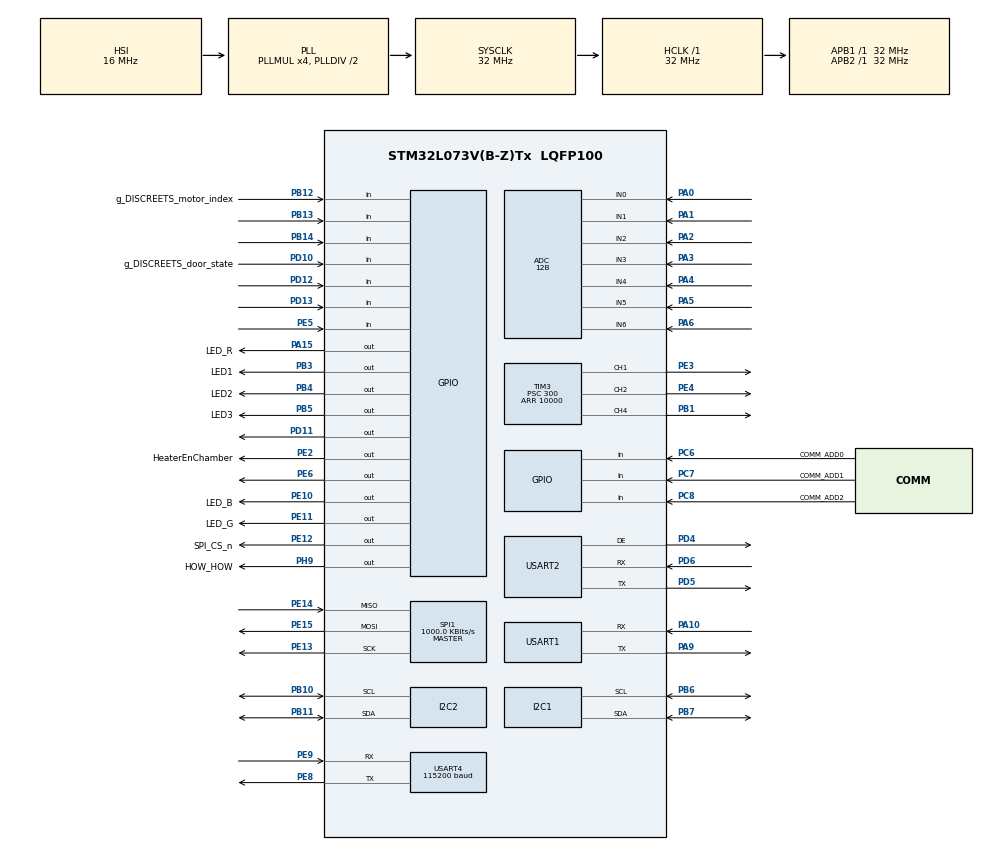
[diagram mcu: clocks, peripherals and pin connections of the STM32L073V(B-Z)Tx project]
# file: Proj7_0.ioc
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ADC.ClockPrescaler=ADC_CLOCK_SYNC_PCLK_DIV2
ADC.ContinuousConvMode=DISABLE
ADC.DMAContinuousRequests=DISABLE
ADC.DataAlign=ADC_DATAALIGN_RIGHT
ADC.DiscontinuousConvMode=DISABLE
ADC.EOCSelection=ADC_EOC_SINGLE_CONV
ADC.EnableAnalogWatchDog=false
ADC.ExternalTrigConv=ADC_SOFTWARE_START
ADC.ExternalTrigConvEdge=ADC_EXTERNALTRIGCONVEDGE_NONE
ADC.LowPowerAutoPowerOff=DISABLE
ADC.LowPowerAutoWait=DISABLE
ADC.LowPowerFrequencyMode=DISABLE
ADC.Overrun=ADC_OVR_DATA_PRESERVED
ADC.OversamplingMode=ENABLE
ADC.Ratio=ADC_OVERSAMPLING_RATIO_16
ADC.Resolution=ADC_RESOLUTION_12B
ADC.RightBitShift=ADC_RIGHTBITSHIFT_4
ADC.SamplingTime=ADC_SAMPLETIME_1CYCLE_5
ADC.ScanConvMode=ADC_SCAN_DIRECTION_FORWARD
Dma.ADC.0.Direction=DMA_PERIPH_TO_MEMORY
Dma.ADC.0.Instance=DMA1_Channel1
Dma.ADC.0.MemDataAlignment=DMA_MDATAALIGN_WORD
Dma.ADC.0.MemInc=DMA_MINC_ENABLE
Dma.ADC.0.Mode=DMA_NORMAL
Dma.ADC.0.PeriphDataAlignment=DMA_PDATAALIGN_HALFWORD
Dma.ADC.0.PeriphInc=DMA_PINC_DISABLE
Dma.ADC.0.Priority=DMA_PRIORITY_HIGH
Dma.Request0=ADC
Dma.Request1=USART1_TX
Dma.Request2=USART2_RX
Dma.Request3=USART2_TX
Dma.USART1_TX.1.Direction=DMA_MEMORY_TO_PERIPH
Dma.USART1_TX.1.Instance=DMA1_Channel2
Dma.USART1_TX.1.MemDataAlignment=DMA_MDATAALIGN_BYTE
Dma.USART1_TX.1.MemInc=DMA_MINC_ENABLE
Dma.USART1_TX.1.Mode=DMA_NORMAL
Dma.USART1_TX.1.PeriphDataAlignment=DMA_PDATAALIGN_BYTE
Dma.USART1_TX.1.PeriphInc=DMA_PINC_DISABLE
Dma.USART1_TX.1.Priority=DMA_PRIORITY_LOW
Dma.USART2_RX.2.Direction=DMA_PERIPH_TO_MEMORY
Dma.USART2_RX.2.Instance=DMA1_Channel5
Dma.USART2_RX.2.MemDataAlignment=DMA_MDATAALIGN_BYTE
Dma.USART2_RX.2.MemInc=DMA_MINC_ENABLE
Dma.USART2_RX.2.Mode=DMA_NORMAL
Dma.USART2_RX.2.PeriphDataAlignment=DMA_PDATAALIGN_BYTE
Dma.USART2_RX.2.PeriphInc=DMA_PINC_DISABLE
Dma.USART2_RX.2.Priority=DMA_PRIORITY_VERY_HIGH
Dma.USART2_TX.3.Direction=DMA_MEMORY_TO_PERIPH
Dma.USART2_TX.3.Instance=DMA1_Channel4
Dma.USART2_TX.3.MemDataAlignment=DMA_MDATAALIGN_BYTE
Dma.USART2_TX.3.MemInc=DMA_MINC_ENABLE
Dma.USART2_TX.3.Mode=DMA_NORMAL
Dma.USART2_TX.3.PeriphDataAlignment=DMA_PDATAALIGN_BYTE
Dma.USART2_TX.3.PeriphInc=DMA_PINC_DISABLE
Dma.USART2_TX.3.Priority=DMA_PRIORITY_LOW
I2C1.Speed=50
I2C1.Timing=0x202029A8
I2C2.Timing=0x00707CBB
Mcu.Family=STM32L0
Mcu.Name=STM32L073V(B-Z)Tx
Mcu.Package=LQFP100
NVIC.DMA1_Channel1_IRQn=true\:0\:0\:false\:false\:true\:false
NVIC.DMA1_Channel2_3_IRQn=true\:0\:0\:false\:false\:true\:false
NVIC.DMA1_Channel4_5_6_7_IRQn=true\:0\:0\:false\:false\:true\:false
NVIC.I2C1_IRQn=true\:0\:0\:false\:false\:true\:true
NVIC.I2C2_IRQn=true\:0\:0\:false\:false\:true\:true
NVIC.USART1_IRQn=true\:0\:0\:false\:false\:true\:true
NVIC.USART2_IRQn=true\:0\:0\:false\:false\:true\:true
NVIC.USART4_5_IRQn=true\:0\:0\:false\:false\:true\:true
PA0.GPIO_Mode=GPIO_MODE_ANALOG
PA0.GPIO_PuPd=GPIO_NOPULL
PA0.Mode=IN0
PA0.Signal=ADC_IN0
PA1.GPIO_Mode=GPIO_MODE_ANALOG
PA1.GPIO_PuPd=GPIO_NOPULL
PA1.Mode=IN1
PA1.Signal=ADC_IN1
PA10.GPIO_ModeDefaultPP=GPIO_MODE_AF_PP
PA10.GPIO_PuPd=GPIO_NOPULL
PA10.GPIO_Speed=GPIO_SPEED_FREQ_VERY_HIGH
PA10.Mode=Asynchronous
PA10.Signal=USART1_RX
PA13.Mode=Serial_Wire
PA13.Signal=SYS_SWDIO
PA14.Mode=Serial_Wire
PA14.Signal=SYS_SWCLK
PA15.GPIO_Label=LED_R
PA15.Signal=GPIO_Output
PA2.GPIO_Mode=GPIO_MODE_ANALOG
PA2.GPIO_PuPd=GPIO_NOPULL
PA2.Mode=IN2
PA2.Signal=ADC_IN2
PA3.GPIO_Mode=GPIO_MODE_ANALOG
PA3.GPIO_PuPd=GPIO_NOPULL
PA3.Mode=IN3
PA3.Signal=ADC_IN3
PA4.GPIO_Mode=GPIO_MODE_ANALOG
PA4.GPIO_PuPd=GPIO_NOPULL
PA4.Mode=IN4
PA4.Signal=ADC_IN4
PA5.GPIO_Mode=GPIO_MODE_ANALOG
PA5.GPIO_PuPd=GPIO_NOPULL
PA5.Mode=IN5
PA5.Signal=ADC_IN5
PA6.GPIO_Mode=GPIO_MODE_ANALOG
PA6.GPIO_PuPd=GPIO_NOPULL
PA6.Mode=IN6
PA6.Signal=ADC_IN6
PA9.Mode=Asynchronous
PA9.Signal=USART1_TX
PB1.GPIO_ModeDefaultPP=GPIO_MODE_AF_PP
PB1.GPIO_PuPd=GPIO_NOPULL
PB1.GPIO_Speed=GPIO_SPEED_FREQ_LOW
PB1.Signal=S_TIM3_CH4
PB10.Mode=I2C
PB10.Signal=I2C2_SCL
PB11.Mode=I2C
PB11.Signal=I2C2_SDA
PB12.GPIO_Label=g_DISCREETS_motor_index
PB12.Signal=GPIO_Input
PB13.GPIO_Mode=GPIO_MODE_INPUT
PB13.GPIO_PuPd=GPIO_NOPULL
PB13.Signal=GPIO_Input
PB14.GPIO_Mode=GPIO_MODE_INPUT
PB14.GPIO_PuPd=GPIO_NOPULL
PB14.Signal=GPIO_Input
PB3.GPIO_Label=LED1
PB3.GPIO_ModeDefaultOutputPP=GPIO_MODE_OUTPUT_PP
PB3.GPIO_PuPd=GPIO_NOPULL
PB3.GPIO_Speed=GPIO_SPEED_FREQ_LOW
PB3.PinState=GPIO_PIN_RESET
PB3.Signal=GPIO_Output
PB4.GPIO_Label=LED2
PB4.GPIO_ModeDefaultOutputPP=GPIO_MODE_OUTPUT_PP
PB4.GPIO_PuPd=GPIO_NOPULL
PB4.GPIO_Speed=GPIO_SPEED_FREQ_LOW
PB4.PinState=GPIO_PIN_RESET
PB4.Signal=GPIO_Output
PB5.GPIO_Label=LED3
PB5.GPIO_ModeDefaultOutputPP=GPIO_MODE_OUTPUT_PP
PB5.GPIO_PuPd=GPIO_NOPULL
PB5.GPIO_Speed=GPIO_SPEED_FREQ_LOW
PB5.PinState=GPIO_PIN_RESET
PB5.Signal=GPIO_Output
PB6.Mode=I2C
PB6.Signal=I2C1_SCL
PB7.Mode=I2C
PB7.Signal=I2C1_SDA
PC6.GPIO_Label=COMM_ADD0
PC6.GPIO_Mode=GPIO_MODE_INPUT
PC6.GPIO_PuPd=GPIO_NOPULL
PC6.Signal=GPIO_Input
PC7.GPIO_Label=COMM_ADD1
PC7.GPIO_Mode=GPIO_MODE_INPUT
PC7.GPIO_PuPd=GPIO_NOPULL
PC7.Signal=GPIO_Input
PC8.GPIO_Label=COMM_ADD2
PC8.GPIO_Mode=GPIO_MODE_INPUT
PC8.GPIO_PuPd=GPIO_NOPULL
PC8.Signal=GPIO_Input
PD10.GPIO_Label=g_DISCREETS_door_state
PD10.GPIO_Mode=GPIO_MODE_INPUT
PD10.GPIO_PuPd=GPIO_NOPULL
PD10.Signal=GPIO_Input
PD11.Signal=GPIO_Output
PD12.Signal=GPIO_Input
PD13.Signal=GPIO_Input
PD4.Mode=Hardware Flow Control (RS485)
PD4.Signal=USART2_DE
PD5.Mode=Asynchronous
PD5.Signal=USART2_TX
PD6.Mode=Asynchronous
PD6.Signal=USART2_RX
PE10.GPIO_Label=LED_B
PE10.Signal=GPIO_Output
PE11.GPIO_Label=LED_G
PE11.Signal=GPIO_Output
PE12.GPIO_Label=SPI_CS_n
PE12.GPIO_ModeDefaultOutputPP=GPIO_MODE_OUTPUT_PP
PE12.GPIO_PuPd=GPIO_NOPULL
PE12.GPIO_Speed=GPIO_SPEED_FREQ_LOW
PE12.PinState=GPIO_PIN_RESET
PE12.Signal=GPIO_Output
PE13.Mode=Full_Duplex_Master
PE13.Signal=SPI1_SCK
PE14.Mode=Full_Duplex_Master
PE14.Signal=SPI1_MISO
PE15.Mode=Full_Duplex_Master
PE15.Signal=SPI1_MOSI
PE2.GPIO_Label=HeaterEnChamber
PE2.GPIO_ModeDefaultOutputPP=GPIO_MODE_OUTPUT_PP
PE2.GPIO_PuPd=GPIO_NOPULL
PE2.GPIO_Speed=GPIO_SPEED_FREQ_LOW
PE2.PinState=GPIO_PIN_SET
PE2.Signal=GPIO_Output
PE3.GPIO_ModeDefaultPP=GPIO_MODE_AF_PP
PE3.GPIO_PuPd=GPIO_NOPULL
PE3.GPIO_Speed=GPIO_SPEED_FREQ_LOW
PE3.Signal=S_TIM3_CH1
PE4.GPIO_ModeDefaultPP=GPIO_MODE_AF_PP
PE4.GPIO_PuPd=GPIO_NOPULL
PE4.GPIO_Speed=GPIO_SPEED_FREQ_LOW
PE4.Signal=S_TIM3_CH2
PE5.Signal=GPIO_Input
PE6.GPIO_ModeDefaultOutputPP=GPIO_MODE_OUTPUT_PP
PE6.GPIO_PuPd=GPIO_NOPULL
PE6.GPIO_Speed=GPIO_SPEED_FREQ_LOW
PE6.PinState=GPIO_PIN_RESET
PE6.Signal=GPIO_Output
PE8.Mode=Asynchronous
PE8.Signal=USART4_TX
PE9.Mode=Asynchronous
PE9.Signal=USART4_RX
PH0-OSC_IN.Mode=HSE-External-Oscillator
PH0-OSC_IN.Signal=RCC_OSC_IN
PH1-OSC_OUT.Mode=HSE-External-Oscillator
PH1-OSC_OUT.Signal=RCC_OSC_OUT
PH9.GPIO_Label=HOW_HOW
PH9.GPIO_ModeDefaultOutputPP=GPIO_MODE_OUTPUT_PP
PH9.GPIO_PuPd=GPIO_NOPULL
PH9.GPIO_Speed=GPIO_SPEED_FREQ_LOW
PH9.PinState=GPIO_PIN_RESET
PH9.Signal=GPIO_Output
ProjectManager.HeapSize=0x200
ProjectManager.StackSize=0x400
ProjectManager.TargetToolchain=MDK-ARM V5
RCC.ADCFreq_Value=16000000
RCC.AHBFreq_Value=32000000
RCC.APB1Freq_Value=32000000
RCC.APB1TimFreq_Value=32000000
RCC.APB2Freq_Value=32000000
RCC.APB2TimFreq_Value=32000000
RCC.HCLKFreq_Value=32000000
RCC.HSE_VALUE=20000000
RCC.HSI16_VALUE=16000000
RCC.HSI48_VALUE=48000000
RCC.HSI_VALUE=16000000
RCC.LSE_VALUE=32768
RCC.MSI_VALUE=2097000
RCC.PLLMUL=RCC_PLLMUL_4
RCC.SYSCLKFreq_VALUE=32000000
RCC.SYSCLKSource=RCC_SYSCLKSOURCE_PLLCLK
RCC.VCOOutputFreq_Value=64000000
SH.S_TIM3_CH1.0=TIM3_CH1,PWM Generation1 CH1
SH.S_TIM3_CH2.0=TIM3_CH2,PWM Generation2 CH2
SH.S_TIM3_CH4.0=TIM3_CH4,PWM Generation4 CH4
SPI1.BaudRatePrescaler=SPI_BAUDRATEPRESCALER_32
SPI1.CalculateBaudRate=1000.0 KBits/s
SPI1.Direction=SPI_DIRECTION_2LINES
SPI1.Mode=SPI_MODE_MASTER
SPI1.VirtualType=VM_MASTER
TIM3.Channel-PWM\ Generation1\ CH1=TIM_CHANNEL_1
TIM3.Channel-PWM\ Generation2\ CH2=TIM_CHANNEL_2
TIM3.Channel-PWM\ Generation4\ CH4=TIM_CHANNEL_4
TIM3.ClockDivision=TIM_CLOCKDIVISION_DIV1
TIM3.CounterMode=TIM_COUNTERMODE_DOWN
TIM3.OCMode_PWM-PWM\ Generation1\ CH1=TIM_OCMODE_PWM1
TIM3.OCMode_PWM-PWM\ Generation2\ CH2=TIM_OCMODE_PWM1
TIM3.OCMode_PWM-PWM\ Generation4\ CH4=TIM_OCMODE_PWM1
TIM3.OCPolarity_1=TIM_OCPOLARITY_LOW
TIM3.OCPolarity_2=TIM_OCPOLARITY_LOW
TIM3.Period=10000
TIM3.Prescaler=300
TIM3.Pulse-PWM\ Generation1\ CH1=0
TIM3.Pulse-PWM\ Generation2\ CH2=0
USART1.VirtualMode-Asynchronous=VM_ASYNC
USART2.VirtualMode-Asynchronous=VM_ASYNC
USART2.VirtualMode-Hardware\ Flow\ Control\ (RS485)=VM_ASYNC
USART4.BaudRate=115200
USART4.VirtualMode-Asynchronous=VM_ASYNC
VP_ADC_Vref_Input.Mode=IN-Vrefint
VP_TIM3_VS_ClockSourceINT.Mode=Internal
board=custom

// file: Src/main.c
/*%%%%%%%%%%%%%%%%%%%%%%%%%%%%%%%%%%%%% INCLUDES %%%%%%%%%%%%%%%%%%%%%%%%%%%%%%%%%%%%% */

#include "main.h"
#include "stm32l0xx_hal.h"

/* USER CODE BEGIN Includes */

#include "host_from_comm.h"
#include "host_to_comm.h"
#include "ADC.h"
#include "heater.h"
#include "motor.h"
#include "rfid.h"
#include "board_temp.h"
#include "ir_temp.h"
#include "error.h"
#include "discreets.h"
#include "init.h"
#include "technician.h"
#include "pid.h"
#include "progress.h"
#include "main.h"
#include "structs.h"

#if 0
  #define SEND_TO_TERMINAL 1
#endif

/* %%%%%%%%%%%%%%%%%%%%%%%%%%%%%%%%%%%% GLOBAL VARIABLES %%%%%%%%%%%%%%%%%%%%%%%%%%%%% */

ADC_HandleTypeDef hadc;
DMA_HandleTypeDef hdma_adc;

I2C_HandleTypeDef hi2c1;
I2C_HandleTypeDef g_MAIN_hi2c2;

SPI_HandleTypeDef hspi1;

TIM_HandleTypeDef htim3;

UART_HandleTypeDef huart1;
UART_HandleTypeDef huart2;
UART_HandleTypeDef huart4;
DMA_HandleTypeDef hdma_usart1_tx;
DMA_HandleTypeDef hdma_usart2_rx;
DMA_HandleTypeDef hdma_usart2_tx;

TIM_OC_InitTypeDef PWM_timer2_OC_params; // structure for controlling PWMs' duty cycles
TIM_OC_InitTypeDef PWM_timer3_OC_params; // structure for controlling PWMs' duty cycles

volatile unsigned short g_MAIN_debug_var0;
volatile unsigned short g_MAIN_uart_tx_callback[5] = {0, 0, 0, 0, 0}; // {0xffff, 0xffff, 0xffff, 0xffff, 0xffff}; // 5 indexes for UART0 to UART4. 0xffff indicates after power on
volatile unsigned short g_MAIN_uart_rx_callback[5] = {0, 0, 0, 0, 0}; // {0xffff, 0xffff, 0xffff, 0xffff, 0xffff}; // 5 indexes for UART0 to UART4

// @@@note: See at main.h defines of comm numbers. Ensure that they fit numbers as deined by CUBE !.

volatile unsigned short g_MAIN_adc_conversion_callback   = 0xffff; // 0xffff for indicating after power on
volatile unsigned short g_MAIN_ir_conversion_callback    = 0xffff; // 0xffff for indicating after power on
volatile unsigned short g_MAIN_temputure_callback  = 0xffff; // 0xffff for indicating after power on

//volatile unsigned short motor_spi_callback = 0xffff;

volatile unsigned short g_MAIN_after_thawing_time = 0;
// counting the time in seconds from end of thawing until door is open.

volatile unsigned int g_MAIN_main_loop_tasks = 0;
// Every bits of this variable when set indicates that a task has to be
// performed in next main loop.  See defines in main.h
// ----------------------------------------------------------------

unsigned short g_MAIN_safety_error = 0;
unsigned short g_MAIN_rfid_count = 0;

extern uint32_t g_ADC_adc_raw_results[NUM_OF_ADC_CHANNELS];
extern uint8_t g_HOST_TO_COMM_som_tx_buffer[C_HOST_TO_COMM_MAX_MSG_LEN_TO_SOM + 5];

extern volatile unsigned short vol0;

extern unsigned short g_RFID_task;
uint8_t g_MAIN_from_rfid_str[C_RFID_STRING_ARRAY_SIZE] = {9, 9, 9};
// contain the entire string returned by the RFID device when it answers a temperature
// measurement request.

uint8_t g_MAIN_pcb_temperature_str[2];
// contain the entire string returned by the board (PCB) temperature measurement device.

extern uint8_t g_HOST_FROM_COMM_som_rx_buffer[C_HOST_FROM_COMM_MAX_MESSAGE_LENGTH];
volatile unsigned short g_MAIN_no_somm_message_timer = 0;
volatile unsigned short g_MAIN_motor_index_timer = 0;
volatile unsigned short g_MAIN_delay_var0 = 0;
volatile unsigned short g_MAIN_timer_20mS_period  = 0; // incremented every   1 mSec, and reset every  20 mSec.
volatile unsigned short g_MAIN_timer_100mS_period = 0; // incremented every  20 mSec, and reset every 100 mSec.
volatile unsigned short g_MAIN_timer_1S_period    = 0; // incremented every 100 mSec, and reset every   1  Sec.
volatile unsigned short one_second_passed_bits = 0;

/*%%%%%%%%%%%%%%%%%%%%%%%%%%%%%%%% LOCAL DECLARATIONS %%%%%%%%%%%%%%%%%%%%%%%%%%%%%%%% */

void SystemClock_Config(void);
static void MX_GPIO_Init(void);
static void MX_DMA_Init(void);
static void MX_ADC_Init(void);
static void MX_I2C1_Init(void);
static void MX_I2C2_Init(void);
static void MX_SPI1_Init(void);
static void MX_TIM3_Init(void);
static void MX_USART1_UART_Init(void);
static void MX_USART2_UART_Init(void);
static void MX_USART4_UART_Init(void);
void HAL_TIM_MspPostInit(TIM_HandleTypeDef *htim);

/*%%%%%%%%%%%%%%%%%%%%%%%%%%%%%%% FUNCTIONS IMPLEMENTATION %%%%%%%%%%%%%%%%%%%%%%%%%%% */

void HAL_SYSTICK_Callback(void)
{
	static unsigned short s1 = 0;

	if (g_MAIN_no_somm_message_timer < 0xfff0)
		g_MAIN_no_somm_message_timer++;

	if (g_MAIN_motor_index_timer < 0xfff0)
		g_MAIN_motor_index_timer++;

	g_MAIN_timer_20mS_period++;
	if (g_MAIN_timer_20mS_period >= 20) {
		g_MAIN_timer_20mS_period = 0;
		g_MAIN_timer_100mS_period++;
		if (g_MAIN_timer_100mS_period == 5) {
			g_MAIN_timer_100mS_period = 0;
			g_MAIN_timer_1S_period++;
			if (g_MAIN_timer_1S_period == 10) {
				g_MAIN_timer_1S_period = 0;
				one_second_passed_bits = 0xffff;
				s1 = 1 - s1; // LED blinking
				if (s1)
					HAL_GPIO_WritePin(LED1_GPIO_Port, LED1_Pin, GPIO_PIN_RESET);
				else
					HAL_GPIO_WritePin(LED1_GPIO_Port, LED1_Pin, GPIO_PIN_SET);
			}
		}
	}

	// Tasks allocation:
	// ----------------
	if (g_MAIN_timer_20mS_period == 0) { // at start of every 20 mSec
		g_MAIN_main_loop_tasks |= ADC_MAIN_LOOP_TASK_BIT;
	}
	else if (g_MAIN_timer_20mS_period == 4) { // at 5th. mS of every 20 mSec
		g_MAIN_main_loop_tasks |= STAGE_UPDATE_MAIN_LOOP_TASK_BIT;
	}
	else if (g_MAIN_timer_20mS_period == 8) { // at 9th. mS of every 20 mSec
		g_MAIN_main_loop_tasks |= SOM_SERVICE_MAIN_LOOP_TASK_BIT;
	}
	else if (g_MAIN_timer_20mS_period ==12) { // at 13th. mS of every 20 mSec
		if (g_MAIN_timer_100mS_period == 0) {
			g_MAIN_main_loop_tasks |= IR_TEMP_MAIN_LOOP_TASK_BIT;
		}
		else if (g_MAIN_timer_100mS_period == 1) {
			g_MAIN_main_loop_tasks |= DOOR_CHECK_MAIN_LOOP_TASK_BIT;
			g_MAIN_main_loop_tasks |= SOM_ADD_UPDATE_MAIN_LOOP_TASK_BIT;
		}
		else if (g_MAIN_timer_100mS_period == 2) {
			g_MAIN_main_loop_tasks |= MOTOR_MAIN_LOOP_TASK_BIT;
		}
		else if (g_MAIN_timer_100mS_period == 3) {
			if (g_MAIN_timer_1S_period == 0) {
				g_MAIN_main_loop_tasks |= PID_CALC_MAIN_LOOP_TASK_BIT;
			}
			else if (g_MAIN_timer_1S_period == 4) {
				g_MAIN_main_loop_tasks |= HEATER_UPDATE_MAIN_LOOP_TASK_BIT;
			}
			else if (g_MAIN_timer_1S_period == 6) {
				g_MAIN_main_loop_tasks |= PCB_TEMP_MAIN_LOOP_TASK_BIT;
			}
			else if (g_MAIN_timer_1S_period == 7) {
				g_MAIN_main_loop_tasks |= DEBUG_TERMINAL_MAIN_LOOP_TASK_BIT;
			}
			else if (g_MAIN_timer_1S_period == 8) { // values of this 100mS timer are 0 to 4. Only 5 values as there are 5 slots of 20mS in 100mS
				g_MAIN_main_loop_tasks |= RFID_TEMP_MAIN_LOOP_TASK_BIT;
			}
		}
	}
}
// --------------------------------------------------------------------------

// --------------------------------------------------------------------------
void HAL_ADC_ConvCpltCallback(ADC_HandleTypeDef* hadc)
{
	if (hadc->Instance == ADC1)
		g_MAIN_adc_conversion_callback = 1;
}
// --------------------------------------------------------------------------

// --------------------------------------------------------------------------
void HAL_I2C_MasterRxCpltCallback(I2C_HandleTypeDef *hi2c)
{
		if (hi2c->Instance == I2C2) // PCB Temperature
			g_MAIN_temputure_callback = 1;
}
// --------------------------------------------------------------------------

// --------------------------------------------------------------------------
/*
void HAL_SPI_TxCpltCallback(SPI_HandleTypeDef *hspi1)
{
	if (hspi1->Instance == SPI1)
		motor_spi_callback = 1;
		HAL_GPIO_WritePin(SPI_CS_n_GPIO_Port, SPI_CS_n_Pin, GPIO_PIN_SET);
}
*/
// --------------------------------------------------------------------------

// --------------------------------------------------------------------------
void HAL_I2C_MemRxCpltCallback(I2C_HandleTypeDef *hi2c)
{
		if (hi2c->Instance == I2C1) // IR
			g_MAIN_ir_conversion_callback = 1;
}
// --------------------------------------------------------------------------

// --------------------------------------------------------------------------
void HAL_UART_TxCpltCallback(UART_HandleTypeDef *huart)
{
	if (huart->Instance == USART1) // debug channel
		g_MAIN_uart_tx_callback[1] = 1;

	if (huart->Instance == USART2) { // If Transmission to SOM ended
		g_MAIN_uart_tx_callback[2] = 1;
		g_MAIN_debug_var0 = 10;
	}

	if (huart->Instance == USART4) // RFID
		g_MAIN_uart_tx_callback[4] = 1;
}
// --------------------------------------------------------------------------

// --------------------------------------------------------------------------
void HAL_UART_RxCpltCallback(UART_HandleTypeDef *huart)
{
	if (huart->Instance == USART1)
		g_MAIN_uart_rx_callback[1] = 1;

	// If data (header or body) was received from SOM:
	// ----------------------------------------------
	if (huart->Instance == USART2) { // Received message from SOM
		g_MAIN_debug_var0 = 11;

		// if just received message header:
		// -------------------------------
		if (system_state.som_comm_state == RECEIVING_MESSAGE_HEADER)
    {
			g_MAIN_debug_var0 = 12;
			system_state.som_comm_state = RECEIVING_MESSAGE_BODY;
			from_som_message_state.message_length = ((uint16_t)g_HOST_FROM_COMM_som_rx_buffer[C_HOST_FROM_COMM_NUM_OF_HEADER_BYTES - 1]);
			if (from_som_message_state.message_length >= (C_HOST_FROM_COMM_MAX_MESSAGE_LENGTH - 2))
				from_som_message_state.message_length = C_HOST_FROM_COMM_NUM_OF_HEADER_BYTES + 5;
//			if (from_som_message_state.message_length == 128)
//				ia11111++; // for debug only
//			if (from_som_message_state.message_length == 31)
//				ia22222++; // for debug only

			// Checking that header is OK:
			// --------------------------
			if ((g_HOST_FROM_COMM_som_rx_buffer[0] != '$') || (g_HOST_FROM_COMM_som_rx_buffer[1] != '$')) { // If error since header does not start with "$$"
				p_INIT_receiving_from_som();
				return;
			}

			// activate DMA to receive message body:
			// ------------------------------------
			g_MAIN_debug_var0 = 13;
			HAL_UART_Receive_DMA(&huart2, &g_HOST_FROM_COMM_som_rx_buffer[C_HOST_FROM_COMM_NUM_OF_HEADER_BYTES], from_som_message_state.message_length - C_HOST_FROM_COMM_NUM_OF_HEADER_BYTES);
			g_MAIN_debug_var0 = 14;
		}

		// if just received message body:
		// -----------------------------
		else if (system_state.som_comm_state == RECEIVING_MESSAGE_BODY)
    {
			g_MAIN_debug_var0 = 15;
			system_state.som_comm_state = COMPLETE_MESSAGE_RECEIVED;
		}
		else
    {
			g_MAIN_debug_var0 = 16;
			system_state.som_comm_state = FAIL;
		}
	}
	// ----------------------------------------------

	if (huart->Instance == USART4)
  {
		g_MAIN_uart_rx_callback[RFID_COMM_UART_NUM] = 1;
	}
}
// --------------------------------------------------------------------------

/* USER CODE END 0 */

int main(void)
{

  /* MCU Configuration----------------------------------------------------------*/

  /* Reset of all peripherals, Initializes the Flash interface and the Systick. */
  HAL_Init();

  /* Configure the system clock */
  SystemClock_Config();

  /* Initialize all configured peripherals */
  MX_GPIO_Init();
  MX_DMA_Init();
  MX_ADC_Init();
  MX_I2C1_Init();
  MX_I2C2_Init();
  MX_SPI1_Init();
  MX_TIM3_Init();
  MX_USART1_UART_Init();
  MX_USART2_UART_Init();
  MX_USART4_UART_Init();
  /* USER CODE BEGIN 2 */

	init();

/* --------------------------------------------------------------------------
 Initializing stepper motor driver
-------------------------------------------------------------------------- */
p_MOTOR_init_L6470();

	// for debug only:
  // --------------
/*
	p_MOTOR_read_agitation_motor_register(0x07, str11111);
	p_MOTOR_read_agitation_motor_register(0x15, str11111);
	p_MOTOR_read_agitation_motor_register(0x06, str11111);
*/
  // --------------

// --------------------------------------------------------------------------

	// Preparing receiving header of the first message after reset:
	// -----------------------------------------------------------
	g_MAIN_no_somm_message_timer = 0;
	HAL_UART_Receive_DMA(&huart2, g_HOST_FROM_COMM_som_rx_buffer, C_HOST_FROM_COMM_NUM_OF_HEADER_BYTES);
	system_state.som_comm_state = RECEIVING_MESSAGE_HEADER;

  /* USER CODE END 2 */

  /* Infinite loop */
  /* USER CODE BEGIN WHILE */
  while (1)
  {

		// if just ended transmission to SOM:
		// ---------------------------------
		if (g_MAIN_uart_tx_callback[SOM_COMM_UART_NUM])
    {
			g_MAIN_uart_tx_callback[SOM_COMM_UART_NUM] = 0;
			p_INIT_receiving_from_som(); // Prepare for receiving new message from SOM
		}

    p_DISCREETS_get_motor_index();

		// If no message from SOM for too long time (time out):
		// ---------------------------------------------------
		if (g_MAIN_no_somm_message_timer >= C_HOST_FROM_COMM_NO_SOM_MESSAGE_TIMO)
    {
			g_MAIN_debug_var0 = 18;
//			MX_USART2_UART_Init();
			system_state.som_comm_state = FAIL;
			HAL_GPIO_WritePin(LED1_GPIO_Port, LED2_Pin, GPIO_PIN_SET);
//		HAL_UART_Receive(&huart2,g_HOST_FROM_COMM_som_rx_buffer, MAX_MESSAGE_LENGTH_FROM_SOM, 5); // Blocking function for empty UART buffer
			p_INIT_receiving_from_som();
		}

//		get_rfid_version(str11111);

		// Getting my SOM comm. address:
		// ----------------------------
		if (g_MAIN_main_loop_tasks & SOM_ADD_UPDATE_MAIN_LOOP_TASK_BIT)
    {
			g_MAIN_debug_var0 = 19;
			g_MAIN_main_loop_tasks &= (~SOM_ADD_UPDATE_MAIN_LOOP_TASK_BIT);
			g_MAIN_debug_var0 = 22;
			system_state.my_som_comm_add = p_DISCREETS_get_som_comm_address();
		}

		// ADCs:
		// ----
		if (g_MAIN_main_loop_tasks & ADC_MAIN_LOOP_TASK_BIT)
    {
			g_MAIN_main_loop_tasks &= (~ADC_MAIN_LOOP_TASK_BIT);

			// If NTC seems disconnected:
			// -------------------------
//		if ((g_ADC_adc_raw_results[NTC_IN_ADC_CHANNEL] < 340) || (g_ADC_adc_raw_results[NTC_OUT_ADC_CHANNEL] < 340)) {
			if ((system_state.ntc_temp[CUSHION0] < (-30)) || (system_state.ntc_temp[CUSHION1] < (-30))) {
				p_ADC_translate_adc(); // for displaying the errorenous values
				if (g_MAIN_safety_error < 1000)
        {
					g_MAIN_safety_error += 5;
				}
				else { // g_MAIN_safety_error >= 1000
					g_MAIN_debug_var0 = 60;
					p_HEATER_update_heaters_power();
					g_MAIN_debug_var0 = 61;
					HAL_GPIO_WritePin(LED1_GPIO_Port, LED3_Pin, GPIO_PIN_SET);
				}
			}

			// if ADC  reading does Not indicate disconnected sensor:
			// -----------------------------------------------------
			else
      {
				if ((g_MAIN_safety_error >= 2) && (g_MAIN_safety_error < 1000))
        {
					g_MAIN_safety_error -= 2;
					g_MAIN_debug_var0 = 62;
				}

				g_MAIN_debug_var0 = 20;

				if (g_MAIN_adc_conversion_callback)
        {
					g_MAIN_adc_conversion_callback = 0;
					g_MAIN_debug_var0 = 63;
				} // @@@wr error code if no call back

			}
			g_MAIN_debug_var0 = 21;
			p_ADC_translate_adc();
			g_MAIN_debug_var0 = 74;
			p_ADC_start_conv();
		}

		// PCB temperature:
		// ---------------
		if (g_MAIN_main_loop_tasks & PCB_TEMP_MAIN_LOOP_TASK_BIT)
    {
			g_MAIN_debug_var0 = 23;
			g_MAIN_main_loop_tasks &= (~PCB_TEMP_MAIN_LOOP_TASK_BIT);
			if (g_MAIN_temputure_callback)
      {
				g_MAIN_temputure_callback = 0;
				g_MAIN_debug_var0 = 24;
			 // @@@wr error code
				system_state.pcb_temp = p_BOAD_TEMP_interpret_pcb_temperature();
				g_MAIN_debug_var0 = 25;
				p_BOAD_TEMP_get_board_temperature(g_MAIN_pcb_temperature_str);
				g_MAIN_debug_var0 = 70;
			}
		}

    // IR temperature sensor:
		// ---------------------
		if (g_MAIN_main_loop_tasks & IR_TEMP_MAIN_LOOP_TASK_BIT)
    {
			g_MAIN_debug_var0 = 26;
			g_MAIN_main_loop_tasks &= (~IR_TEMP_MAIN_LOOP_TASK_BIT);
			if (g_MAIN_ir_conversion_callback)
      {
				g_MAIN_ir_conversion_callback = 0;
				g_MAIN_debug_var0 = 27;
				system_state.ir_temp = p_IR_TEMP_interpret_ir_temperature();
				g_MAIN_debug_var0 = 28;
				p_IR_TEMP_get_temperature();
			}
		}

		// RFID temperature sensor:
		// -----------------------
		if (g_MAIN_main_loop_tasks & RFID_TEMP_MAIN_LOOP_TASK_BIT)
    {
			g_MAIN_main_loop_tasks &= (~RFID_TEMP_MAIN_LOOP_TASK_BIT);
			g_MAIN_rfid_count++;
			if (g_MAIN_rfid_count >= 3)
      {
				g_MAIN_rfid_count = 0;

				g_MAIN_debug_var0 = 29;
				if (g_MAIN_uart_rx_callback[RFID_COMM_UART_NUM]) { // If was answer (any answer) from RFID
					g_MAIN_uart_rx_callback[RFID_COMM_UART_NUM] = 0;
					g_MAIN_debug_var0 = 31;
					switch(g_RFID_task)
          {
						case C_RFID_READ_TEMPERATURE_RFID_TASK:
							g_MAIN_debug_var0 = 32;
							system_state.rfid_temp = rfid_temp_ascii_to_int();
							g_MAIN_debug_var0 = 33;
							p_RFID_get_temperature(g_MAIN_from_rfid_str);
							g_MAIN_debug_var0 = 34;
							break;
						case C_RFID_READ_COUNTER_RFID_TASK:
							g_MAIN_debug_var0 = 35;
							p_RFID_get_temperature(g_MAIN_from_rfid_str); // @@@note changed to temperature reading
							g_MAIN_debug_var0 = 36;
							break;
						default:
							g_MAIN_debug_var0 = 81;
							p_RFID_get_temperature(g_MAIN_from_rfid_str); // @@@note changed to temperature reading
							g_MAIN_debug_var0 = 82;
							break;
					}
				}
				else { // If was no CallBack
					g_MAIN_debug_var0 = 81;
					system_state.rfid_temp = C_RFID_NO_ANSWER_RETURNED_TEMPERATURE; // 88.8 C indicate no answer from RFID
					p_RFID_get_temperature(g_MAIN_from_rfid_str);
					g_MAIN_debug_var0 = 82;
				}
			}
		}

		// Check the door state:
		// --------------------
		if (g_MAIN_main_loop_tasks & DOOR_CHECK_MAIN_LOOP_TASK_BIT)
    {
			g_MAIN_debug_var0 = 37;
			g_MAIN_main_loop_tasks &= (~DOOR_CHECK_MAIN_LOOP_TASK_BIT);
			p_DISCREETS_get_door_state();
			g_MAIN_debug_var0 = 38;
		}

#ifdef SEND_TO_TERMINAL
		// If data transmision to debug UART is compleeted:
		// -----------------------------------------------
		if (g_MAIN_main_loop_tasks & DEBUG_TERMINAL_MAIN_LOOP_TASK_BIT) {
			g_MAIN_debug_var0 = 39;
			g_MAIN_main_loop_tasks &= (~DEBUG_TERMINAL_MAIN_LOOP_TASK_BIT);
			g_MAIN_uart_tx_callback[DEBUG_COMM_UART_NUM] = 0;
				p_TECHNICIAN_send_debug_values();
			g_MAIN_debug_var0 = 40;
		}
#endif

		// Stage and Progress:
		// ------------------
		if (g_MAIN_main_loop_tasks & STAGE_UPDATE_MAIN_LOOP_TASK_BIT) {
			g_MAIN_debug_var0 = 41;
			g_MAIN_main_loop_tasks &= (~STAGE_UPDATE_MAIN_LOOP_TASK_BIT);
			p_PROGRESS_stage_and_rpogress();
			g_MAIN_debug_var0 = 42;
		}

		// Calculate PID:
		// -------------
		if (g_MAIN_main_loop_tasks & PID_CALC_MAIN_LOOP_TASK_BIT) {
			g_MAIN_debug_var0 = 43;
			g_MAIN_main_loop_tasks &= (~PID_CALC_MAIN_LOOP_TASK_BIT);
			g_PID_calc_pid();
			g_MAIN_debug_var0 = 44;
		}

		// Update PWMs of heating elements:
		// -------------------------------
		if (g_MAIN_main_loop_tasks & HEATER_UPDATE_MAIN_LOOP_TASK_BIT) {
			g_MAIN_debug_var0 = 45;
			g_MAIN_main_loop_tasks &= (~HEATER_UPDATE_MAIN_LOOP_TASK_BIT);
			p_HEATER_update_heaters_power();
			g_MAIN_debug_var0 = 46;
		}

		// Update agitation motor speed and check ADC calibration:
		// ------------------------------------------------------
		if (g_MAIN_main_loop_tasks & MOTOR_MAIN_LOOP_TASK_BIT) {
			g_MAIN_debug_var0 = 47;
			g_MAIN_main_loop_tasks &= (~MOTOR_MAIN_LOOP_TASK_BIT);
			p_MOTOR_update_agitation_motor_speed();
			g_MAIN_debug_var0 = 48;

			p_ADC_calib();
			g_MAIN_debug_var0 = 49;
		}

		// Serve communication with host for the case a message was received:
		// -----------------------------------------------------------------
//		if (g_MAIN_main_loop_tasks & SOM_SERVICE_MAIN_LOOP_TASK_BIT) {
//			g_MAIN_debug_var0 = 50;
//			g_MAIN_main_loop_tasks &= (~SOM_SERVICE_MAIN_LOOP_TASK_BIT);
			p_HOST_FROM_COMM_serve_host_comm();
//			g_MAIN_debug_var0 = 51;
//		}

		// Check and treat errors:
		// ----------------------
		p_ERROR_top();
		g_MAIN_debug_var0 = 52;

		// Watchdog triggerring:
		// --------------------
		HAL_GPIO_WritePin(HOW_HOW_GPIO_Port, HOW_HOW_Pin, GPIO_PIN_SET);
		g_MAIN_delay_var0++;
		g_MAIN_delay_var0++;
		HAL_GPIO_WritePin(HOW_HOW_GPIO_Port, HOW_HOW_Pin, GPIO_PIN_RESET);

  /* USER CODE END WHILE */

  }

}

/*%%%%%%%%%%%%%%%%%%%%%%%%%%%%%%%% Init routines %%%%%%%%%%%%%%%%%%%%%%%%%%%%%%%% */

void SystemClock_Config(void)
{

  RCC_OscInitTypeDef RCC_OscInitStruct;
  RCC_ClkInitTypeDef RCC_ClkInitStruct;
  RCC_PeriphCLKInitTypeDef PeriphClkInit;

    /**Configure the main internal regulator output voltage
    */
  __HAL_PWR_VOLTAGESCALING_CONFIG(PWR_REGULATOR_VOLTAGE_SCALE1);

    /**Initializes the CPU, AHB and APB busses clocks
    */
  RCC_OscInitStruct.OscillatorType = RCC_OSCILLATORTYPE_HSI;
  RCC_OscInitStruct.HSIState = RCC_HSI_ON;
  RCC_OscInitStruct.HSICalibrationValue = 16;
  RCC_OscInitStruct.PLL.PLLState = RCC_PLL_ON;
  RCC_OscInitStruct.PLL.PLLSource = RCC_PLLSOURCE_HSI;
  RCC_OscInitStruct.PLL.PLLMUL = RCC_PLLMUL_4;
  RCC_OscInitStruct.PLL.PLLDIV = RCC_PLLDIV_2;
  if (HAL_RCC_OscConfig(&RCC_OscInitStruct) != HAL_OK)
  {
    _Error_Handler(__FILE__, __LINE__);
  }

    /**Initializes the CPU, AHB and APB busses clocks
    */
  RCC_ClkInitStruct.ClockType = RCC_CLOCKTYPE_HCLK|RCC_CLOCKTYPE_SYSCLK
                              |RCC_CLOCKTYPE_PCLK1|RCC_CLOCKTYPE_PCLK2;
  RCC_ClkInitStruct.SYSCLKSource = RCC_SYSCLKSOURCE_PLLCLK;
  RCC_ClkInitStruct.AHBCLKDivider = RCC_SYSCLK_DIV1;
  RCC_ClkInitStruct.APB1CLKDivider = RCC_HCLK_DIV1;
  RCC_ClkInitStruct.APB2CLKDivider = RCC_HCLK_DIV1;

  if (HAL_RCC_ClockConfig(&RCC_ClkInitStruct, FLASH_LATENCY_1) != HAL_OK)
  {
    _Error_Handler(__FILE__, __LINE__);
  }

  PeriphClkInit.PeriphClockSelection = RCC_PERIPHCLK_USART1|RCC_PERIPHCLK_USART2
                              |RCC_PERIPHCLK_I2C1;
  PeriphClkInit.Usart1ClockSelection = RCC_USART1CLKSOURCE_PCLK2;
  PeriphClkInit.Usart2ClockSelection = RCC_USART2CLKSOURCE_PCLK1;
  PeriphClkInit.I2c1ClockSelection = RCC_I2C1CLKSOURCE_PCLK1;
  if (HAL_RCCEx_PeriphCLKConfig(&PeriphClkInit) != HAL_OK)
  {
    _Error_Handler(__FILE__, __LINE__);
  }

    /**Configure the Systick interrupt time
    */
  HAL_SYSTICK_Config(HAL_RCC_GetHCLKFreq()/1000);

    /**Configure the Systick
    */
  HAL_SYSTICK_CLKSourceConfig(SYSTICK_CLKSOURCE_HCLK);

  /* SysTick_IRQn interrupt configuration */
  HAL_NVIC_SetPriority(SysTick_IRQn, 0, 0);
}

/* ADC init function */
static void MX_ADC_Init(void)
{

  ADC_ChannelConfTypeDef sConfig;

    /**Configure the global features of the ADC (Clock, Resolution, Data Alignment and number of conversion)
    */
  hadc.Instance = ADC1;
  hadc.Init.OversamplingMode = ENABLE;
  hadc.Init.Oversample.Ratio = ADC_OVERSAMPLING_RATIO_16;
  hadc.Init.Oversample.RightBitShift = ADC_RIGHTBITSHIFT_4;
  hadc.Init.Oversample.TriggeredMode = ADC_TRIGGEREDMODE_SINGLE_TRIGGER;
  hadc.Init.ClockPrescaler = ADC_CLOCK_SYNC_PCLK_DIV2;
  hadc.Init.Resolution = ADC_RESOLUTION_12B;
  hadc.Init.SamplingTime = ADC_SAMPLETIME_1CYCLE_5;
  hadc.Init.ScanConvMode = ADC_SCAN_DIRECTION_FORWARD;
  hadc.Init.DataAlign = ADC_DATAALIGN_RIGHT;
  hadc.Init.ContinuousConvMode = DISABLE;
  hadc.Init.DiscontinuousConvMode = DISABLE;
  hadc.Init.ExternalTrigConvEdge = ADC_EXTERNALTRIGCONVEDGE_NONE;
  hadc.Init.ExternalTrigConv = ADC_SOFTWARE_START;
  hadc.Init.DMAContinuousRequests = DISABLE;
  hadc.Init.EOCSelection = ADC_EOC_SINGLE_CONV;
  hadc.Init.Overrun = ADC_OVR_DATA_PRESERVED;
  hadc.Init.LowPowerAutoWait = DISABLE;
  hadc.Init.LowPowerFrequencyMode = DISABLE;
  hadc.Init.LowPowerAutoPowerOff = DISABLE;
  if (HAL_ADC_Init(&hadc) != HAL_OK)
  {
    _Error_Handler(__FILE__, __LINE__);
  }

    /**Configure for the selected ADC regular channel to be converted.
    */
  sConfig.Channel = ADC_CHANNEL_0;
  sConfig.Rank = ADC_RANK_CHANNEL_NUMBER;
  if (HAL_ADC_ConfigChannel(&hadc, &sConfig) != HAL_OK)
  {
    _Error_Handler(__FILE__, __LINE__);
  }

    /**Configure for the selected ADC regular channel to be converted.
    */
  sConfig.Channel = ADC_CHANNEL_1;
  if (HAL_ADC_ConfigChannel(&hadc, &sConfig) != HAL_OK)
  {
    _Error_Handler(__FILE__, __LINE__);
  }

    /**Configure for the selected ADC regular channel to be converted.
    */
  sConfig.Channel = ADC_CHANNEL_2;
  if (HAL_ADC_ConfigChannel(&hadc, &sConfig) != HAL_OK)
  {
    _Error_Handler(__FILE__, __LINE__);
  }

    /**Configure for the selected ADC regular channel to be converted.
    */
  sConfig.Channel = ADC_CHANNEL_3;
  if (HAL_ADC_ConfigChannel(&hadc, &sConfig) != HAL_OK)
  {
    _Error_Handler(__FILE__, __LINE__);
  }

    /**Configure for the selected ADC regular channel to be converted.
    */
  sConfig.Channel = ADC_CHANNEL_4;
  if (HAL_ADC_ConfigChannel(&hadc, &sConfig) != HAL_OK)
  {
    _Error_Handler(__FILE__, __LINE__);
  }

    /**Configure for the selected ADC regular channel to be converted.
    */
  sConfig.Channel = ADC_CHANNEL_5;
  if (HAL_ADC_ConfigChannel(&hadc, &sConfig) != HAL_OK)
  {
    _Error_Handler(__FILE__, __LINE__);
  }

    /**Configure for the selected ADC regular channel to be converted.
    */
  sConfig.Channel = ADC_CHANNEL_6;
  if (HAL_ADC_ConfigChannel(&hadc, &sConfig) != HAL_OK)
  {
    _Error_Handler(__FILE__, __LINE__);
  }

    /**Configure for the selected ADC regular channel to be converted.
    */
  sConfig.Channel = ADC_CHANNEL_VREFINT;
  if (HAL_ADC_ConfigChannel(&hadc, &sConfig) != HAL_OK)
  {
    _Error_Handler(__FILE__, __LINE__);
  }

}

/* I2C1 init function */
static void MX_I2C1_Init(void)
{

  hi2c1.Instance = I2C1;
  hi2c1.Init.Timing = 0x202029A8;
  hi2c1.Init.OwnAddress1 = 0;
  hi2c1.Init.AddressingMode = I2C_ADDRESSINGMODE_7BIT;
  hi2c1.Init.DualAddressMode = I2C_DUALADDRESS_DISABLE;
  hi2c1.Init.OwnAddress2 = 0;
  hi2c1.Init.OwnAddress2Masks = I2C_OA2_NOMASK;
  hi2c1.Init.GeneralCallMode = I2C_GENERALCALL_DISABLE;
  hi2c1.Init.NoStretchMode = I2C_NOSTRETCH_DISABLE;
  if (HAL_I2C_Init(&hi2c1) != HAL_OK)
  {
    _Error_Handler(__FILE__, __LINE__);
  }

    /**Configure Analogue filter
    */
  if (HAL_I2CEx_ConfigAnalogFilter(&hi2c1, I2C_ANALOGFILTER_ENABLE) != HAL_OK)
  {
    _Error_Handler(__FILE__, __LINE__);
  }

    /**Configure Digital filter
    */
  if (HAL_I2CEx_ConfigDigitalFilter(&hi2c1, 0) != HAL_OK)
  {
    _Error_Handler(__FILE__, __LINE__);
  }

}

/* I2C2 init function */
static void MX_I2C2_Init(void)
{

  g_MAIN_hi2c2.Instance = I2C2;
  g_MAIN_hi2c2.Init.Timing = 0x00707CBB;
  g_MAIN_hi2c2.Init.OwnAddress1 = 0;
  g_MAIN_hi2c2.Init.AddressingMode = I2C_ADDRESSINGMODE_7BIT;
  g_MAIN_hi2c2.Init.DualAddressMode = I2C_DUALADDRESS_DISABLE;
  g_MAIN_hi2c2.Init.OwnAddress2 = 0;
  g_MAIN_hi2c2.Init.OwnAddress2Masks = I2C_OA2_NOMASK;
  g_MAIN_hi2c2.Init.GeneralCallMode = I2C_GENERALCALL_DISABLE;
  g_MAIN_hi2c2.Init.NoStretchMode = I2C_NOSTRETCH_DISABLE;
  if (HAL_I2C_Init(&g_MAIN_hi2c2) != HAL_OK)
  {
    _Error_Handler(__FILE__, __LINE__);
  }

    /**Configure Analogue filter
    */
  if (HAL_I2CEx_ConfigAnalogFilter(&g_MAIN_hi2c2, I2C_ANALOGFILTER_ENABLE) != HAL_OK)
  {
    _Error_Handler(__FILE__, __LINE__);
  }

    /**Configure Digital filter
    */
  if (HAL_I2CEx_ConfigDigitalFilter(&g_MAIN_hi2c2, 0) != HAL_OK)
  {
    _Error_Handler(__FILE__, __LINE__);
  }

}

/* SPI1 init function */
static void MX_SPI1_Init(void)
{

  /* SPI1 parameter configuration*/
  hspi1.Instance = SPI1;
  hspi1.Init.Mode = SPI_MODE_MASTER;
  hspi1.Init.Direction = SPI_DIRECTION_2LINES;
  hspi1.Init.DataSize = SPI_DATASIZE_8BIT;
  hspi1.Init.CLKPolarity = SPI_POLARITY_LOW;
  hspi1.Init.CLKPhase = SPI_PHASE_1EDGE;
  hspi1.Init.NSS = SPI_NSS_SOFT;
  hspi1.Init.BaudRatePrescaler = SPI_BAUDRATEPRESCALER_32;
  hspi1.Init.FirstBit = SPI_FIRSTBIT_MSB;
  hspi1.Init.TIMode = SPI_TIMODE_DISABLE;
  hspi1.Init.CRCCalculation = SPI_CRCCALCULATION_DISABLE;
  hspi1.Init.CRCPolynomial = 7;
  if (HAL_SPI_Init(&hspi1) != HAL_OK)
  {
    _Error_Handler(__FILE__, __LINE__);
  }

}

/* TIM3 init function */
static void MX_TIM3_Init(void)
{

  TIM_ClockConfigTypeDef sClockSourceConfig;
  TIM_MasterConfigTypeDef sMasterConfig;
  TIM_OC_InitTypeDef sConfigOC;

  htim3.Instance = TIM3;
  htim3.Init.Prescaler = 300;
  htim3.Init.CounterMode = TIM_COUNTERMODE_DOWN;
  htim3.Init.Period = 10000;
  htim3.Init.ClockDivision = TIM_CLOCKDIVISION_DIV1;
  if (HAL_TIM_Base_Init(&htim3) != HAL_OK)
  {
    _Error_Handler(__FILE__, __LINE__);
  }

  sClockSourceConfig.ClockSource = TIM_CLOCKSOURCE_INTERNAL;
  if (HAL_TIM_ConfigClockSource(&htim3, &sClockSourceConfig) != HAL_OK)
  {
    _Error_Handler(__FILE__, __LINE__);
  }

  if (HAL_TIM_PWM_Init(&htim3) != HAL_OK)
  {
    _Error_Handler(__FILE__, __LINE__);
  }

  sMasterConfig.MasterOutputTrigger = TIM_TRGO_RESET;
  sMasterConfig.MasterSlaveMode = TIM_MASTERSLAVEMODE_DISABLE;
  if (HAL_TIMEx_MasterConfigSynchronization(&htim3, &sMasterConfig) != HAL_OK)
  {
    _Error_Handler(__FILE__, __LINE__);
  }

  sConfigOC.OCMode = TIM_OCMODE_PWM1;
  sConfigOC.Pulse = 0;
  sConfigOC.OCPolarity = TIM_OCPOLARITY_LOW;
  sConfigOC.OCFastMode = TIM_OCFAST_DISABLE;
  if (HAL_TIM_PWM_ConfigChannel(&htim3, &sConfigOC, TIM_CHANNEL_1) != HAL_OK)
  {
    _Error_Handler(__FILE__, __LINE__);
  }

  if (HAL_TIMEx_RemapConfig(&htim3, TIM3_TI1_GPIO) != HAL_OK)
  {
    _Error_Handler(__FILE__, __LINE__);
  }

  if (HAL_TIM_PWM_ConfigChannel(&htim3, &sConfigOC, TIM_CHANNEL_2) != HAL_OK)
  {
    _Error_Handler(__FILE__, __LINE__);
  }

  sConfigOC.OCPolarity = TIM_OCPOLARITY_HIGH;
  if (HAL_TIM_PWM_ConfigChannel(&htim3, &sConfigOC, TIM_CHANNEL_4) != HAL_OK)
  {
    _Error_Handler(__FILE__, __LINE__);
  }

  HAL_TIM_MspPostInit(&htim3);

}

/* USART1 init function */
static void MX_USART1_UART_Init(void)
{

  huart1.Instance = USART1;
  huart1.Init.BaudRate = 115200;
  huart1.Init.WordLength = UART_WORDLENGTH_8B;
  huart1.Init.StopBits = UART_STOPBITS_1;
  huart1.Init.Parity = UART_PARITY_NONE;
  huart1.Init.Mode = UART_MODE_TX_RX;
  huart1.Init.HwFlowCtl = UART_HWCONTROL_NONE;
  huart1.Init.OverSampling = UART_OVERSAMPLING_16;
  huart1.Init.OneBitSampling = UART_ONE_BIT_SAMPLE_DISABLE;
  huart1.AdvancedInit.AdvFeatureInit = UART_ADVFEATURE_NO_INIT;
  if (HAL_UART_Init(&huart1) != HAL_OK)
  {
    _Error_Handler(__FILE__, __LINE__);
  }

}

/* USART2 init function */
static void MX_USART2_UART_Init(void)
{

  huart2.Instance = USART2;
  huart2.Init.BaudRate = 115200;
  huart2.Init.WordLength = UART_WORDLENGTH_8B;
  huart2.Init.StopBits = UART_STOPBITS_1;
  huart2.Init.Parity = UART_PARITY_NONE;
  huart2.Init.Mode = UART_MODE_TX_RX;
  huart2.Init.HwFlowCtl = UART_HWCONTROL_NONE;
  huart2.Init.OverSampling = UART_OVERSAMPLING_16;
  huart2.Init.OneBitSampling = UART_ONE_BIT_SAMPLE_DISABLE;
  huart2.AdvancedInit.AdvFeatureInit = UART_ADVFEATURE_NO_INIT;
  if (HAL_RS485Ex_Init(&huart2, UART_DE_POLARITY_HIGH, 0, 0) != HAL_OK)
  {
    _Error_Handler(__FILE__, __LINE__);
  }

}

/* USART4 init function */
static void MX_USART4_UART_Init(void)
{

  huart4.Instance = USART4;
  huart4.Init.BaudRate = 115200;
  huart4.Init.WordLength = UART_WORDLENGTH_8B;
  huart4.Init.StopBits = UART_STOPBITS_1;
  huart4.Init.Parity = UART_PARITY_NONE;
  huart4.Init.Mode = UART_MODE_TX_RX;
  huart4.Init.HwFlowCtl = UART_HWCONTROL_NONE;
  huart4.Init.OverSampling = UART_OVERSAMPLING_16;
  huart4.Init.OneBitSampling = UART_ONE_BIT_SAMPLE_DISABLE;
  huart4.AdvancedInit.AdvFeatureInit = UART_ADVFEATURE_NO_INIT;
  if (HAL_UART_Init(&huart4) != HAL_OK)
  {
    _Error_Handler(__FILE__, __LINE__);
  }

}

static void MX_DMA_Init(void)
{
  /* DMA controller clock enable */
  __HAL_RCC_DMA1_CLK_ENABLE();

  /* DMA interrupt init */
  /* DMA1_Channel1_IRQn interrupt configuration */
  HAL_NVIC_SetPriority(DMA1_Channel1_IRQn, 0, 0);
  HAL_NVIC_EnableIRQ(DMA1_Channel1_IRQn);
  /* DMA1_Channel2_3_IRQn interrupt configuration */
  HAL_NVIC_SetPriority(DMA1_Channel2_3_IRQn, 0, 0);
  HAL_NVIC_EnableIRQ(DMA1_Channel2_3_IRQn);
  /* DMA1_Channel4_5_6_7_IRQn interrupt configuration */
  HAL_NVIC_SetPriority(DMA1_Channel4_5_6_7_IRQn, 0, 0);
  HAL_NVIC_EnableIRQ(DMA1_Channel4_5_6_7_IRQn);

}

/** Configure pins as
        * Analog
        * Input
        * Output
        * EVENT_OUT
        * EXTI
*/
static void MX_GPIO_Init(void)
{

  GPIO_InitTypeDef GPIO_InitStruct;

  /* GPIO Ports Clock Enable */
  __HAL_RCC_GPIOE_CLK_ENABLE();
  __HAL_RCC_GPIOH_CLK_ENABLE();
  __HAL_RCC_GPIOA_CLK_ENABLE();
  __HAL_RCC_GPIOB_CLK_ENABLE();
  __HAL_RCC_GPIOD_CLK_ENABLE();
  __HAL_RCC_GPIOC_CLK_ENABLE();

  /*Configure GPIO pin Output Level */
  HAL_GPIO_WritePin(HeaterEnChamber_GPIO_Port, HeaterEnChamber_Pin, GPIO_PIN_SET);

  /*Configure GPIO pin Output Level */
  HAL_GPIO_WritePin(GPIOE, GPIO_PIN_6|LED_B_Pin|LED_G_Pin|SPI_CS_n_Pin, GPIO_PIN_RESET);

  /*Configure GPIO pin Output Level */
  HAL_GPIO_WritePin(HOW_HOW_GPIO_Port, HOW_HOW_Pin, GPIO_PIN_RESET);

  /*Configure GPIO pin Output Level */
  HAL_GPIO_WritePin(GPIOD, GPIO_PIN_11, GPIO_PIN_RESET);

  /*Configure GPIO pin Output Level */
  HAL_GPIO_WritePin(LED_R_GPIO_Port, LED_R_Pin, GPIO_PIN_RESET);

  /*Configure GPIO pin Output Level */
  HAL_GPIO_WritePin(GPIOB, LED1_Pin|LED2_Pin|LED3_Pin, GPIO_PIN_RESET);

  /*Configure GPIO pins : HeaterEnChamber_Pin PE6 LED_B_Pin LED_G_Pin
                           SPI_CS_n_Pin */
  GPIO_InitStruct.Pin = HeaterEnChamber_Pin|GPIO_PIN_6|LED_B_Pin|LED_G_Pin
                          |SPI_CS_n_Pin;
  GPIO_InitStruct.Mode = GPIO_MODE_OUTPUT_PP;
  GPIO_InitStruct.Pull = GPIO_NOPULL;
  GPIO_InitStruct.Speed = GPIO_SPEED_FREQ_LOW;
  HAL_GPIO_Init(GPIOE, &GPIO_InitStruct);

  /*Configure GPIO pin : PE5 */
  GPIO_InitStruct.Pin = GPIO_PIN_5;
  GPIO_InitStruct.Mode = GPIO_MODE_INPUT;
  GPIO_InitStruct.Pull = GPIO_NOPULL;
  HAL_GPIO_Init(GPIOE, &GPIO_InitStruct);

  /*Configure GPIO pin : HOW_HOW_Pin */
  GPIO_InitStruct.Pin = HOW_HOW_Pin;
  GPIO_InitStruct.Mode = GPIO_MODE_OUTPUT_PP;
  GPIO_InitStruct.Pull = GPIO_NOPULL;
  GPIO_InitStruct.Speed = GPIO_SPEED_FREQ_LOW;
  HAL_GPIO_Init(HOW_HOW_GPIO_Port, &GPIO_InitStruct);

  /*Configure GPIO pins : MOTOR_INDEX_Pin PB13 PB14 */
  GPIO_InitStruct.Pin = MOTOR_INDEX_Pin|GPIO_PIN_13|GPIO_PIN_14;
  GPIO_InitStruct.Mode = GPIO_MODE_INPUT;
  GPIO_InitStruct.Pull = GPIO_NOPULL;
  HAL_GPIO_Init(GPIOB, &GPIO_InitStruct);

  /*Configure GPIO pins : DOOR_STATE_Pin PD12 PD13 */
  GPIO_InitStruct.Pin = DOOR_STATE_Pin|GPIO_PIN_12|GPIO_PIN_13;
  GPIO_InitStruct.Mode = GPIO_MODE_INPUT;
  GPIO_InitStruct.Pull = GPIO_NOPULL;
  HAL_GPIO_Init(GPIOD, &GPIO_InitStruct);

  /*Configure GPIO pin : PD11 */
  GPIO_InitStruct.Pin = GPIO_PIN_11;
  GPIO_InitStruct.Mode = GPIO_MODE_OUTPUT_PP;
  GPIO_InitStruct.Pull = GPIO_NOPULL;
  GPIO_InitStruct.Speed = GPIO_SPEED_FREQ_LOW;
  HAL_GPIO_Init(GPIOD, &GPIO_InitStruct);

  /*Configure GPIO pins : COMM_ADD0_Pin COMM_ADD1_Pin COMM_ADD2_Pin */
  GPIO_InitStruct.Pin = COMM_ADD0_Pin|COMM_ADD1_Pin|COMM_ADD2_Pin;
  GPIO_InitStruct.Mode = GPIO_MODE_INPUT;
  GPIO_InitStruct.Pull = GPIO_NOPULL;
  HAL_GPIO_Init(GPIOC, &GPIO_InitStruct);

  /*Configure GPIO pin : LED_R_Pin */
  GPIO_InitStruct.Pin = LED_R_Pin;
  GPIO_InitStruct.Mode = GPIO_MODE_OUTPUT_PP;
  GPIO_InitStruct.Pull = GPIO_NOPULL;
  GPIO_InitStruct.Speed = GPIO_SPEED_FREQ_LOW;
  HAL_GPIO_Init(LED_R_GPIO_Port, &GPIO_InitStruct);

  /*Configure GPIO pins : LED1_Pin LED2_Pin LED3_Pin */
  GPIO_InitStruct.Pin = LED1_Pin|LED2_Pin|LED3_Pin;
  GPIO_InitStruct.Mode = GPIO_MODE_OUTPUT_PP;
  GPIO_InitStruct.Pull = GPIO_NOPULL;
  GPIO_InitStruct.Speed = GPIO_SPEED_FREQ_LOW;
  HAL_GPIO_Init(GPIOB, &GPIO_InitStruct);

}

void _Error_Handler(char *file, int line)
{
  while(1)
  {
  }
}
